One B-rep face of a CAD part: STEP entity #25646.
In plain terms, the planar face has unit normal (0, 0, 1).
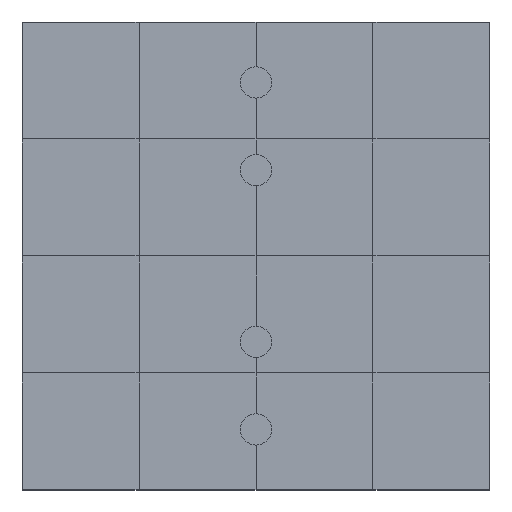
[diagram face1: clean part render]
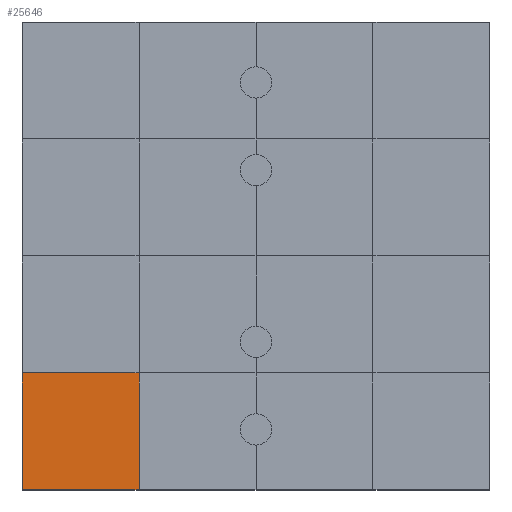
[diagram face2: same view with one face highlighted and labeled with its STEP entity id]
Its self-contained STEP definition (entity closure, numbers rounded to 3 decimals):
#25457 = VERTEX_POINT('',#25458);
#25458 = CARTESIAN_POINT('',(0.,0.,1.5));
#25465 = PLANE('',#25466);
#25466 = AXIS2_PLACEMENT_3D('',#25467,#25468,#25469);
#25467 = CARTESIAN_POINT('',(0.,0.,0.));
#25468 = DIRECTION('',(1.,0.,-0.));
#25469 = DIRECTION('',(0.,0.,1.));
#25477 = PLANE('',#25478);
#25478 = AXIS2_PLACEMENT_3D('',#25479,#25480,#25481);
#25479 = CARTESIAN_POINT('',(0.,0.,0.));
#25480 = DIRECTION('',(-0.,1.,0.));
#25481 = DIRECTION('',(0.,0.,1.));
#25518 = VERTEX_POINT('',#25519);
#25519 = CARTESIAN_POINT('',(0.,3.,1.5));
#25545 = EDGE_CURVE('',#25457,#25518,#25546,.T.);
#25546 = SURFACE_CURVE('',#25547,(#25551,#25558),.PCURVE_S1.);
#25547 = LINE('',#25548,#25549);
#25548 = CARTESIAN_POINT('',(0.,0.,1.5));
#25549 = VECTOR('',#25550,1.);
#25550 = DIRECTION('',(-0.,1.,0.));
#25551 = PCURVE('',#25465,#25552);
#25552 = DEFINITIONAL_REPRESENTATION('',(#25553),#25557);
#25553 = LINE('',#25554,#25555);
#25554 = CARTESIAN_POINT('',(1.5,0.));
#25555 = VECTOR('',#25556,1.);
#25556 = DIRECTION('',(0.,-1.));
#25557 = ( GEOMETRIC_REPRESENTATION_CONTEXT(2) 
PARAMETRIC_REPRESENTATION_CONTEXT() REPRESENTATION_CONTEXT('2D SPACE',''
  ) );
#25558 = PCURVE('',#25559,#25564);
#25559 = PLANE('',#25560);
#25560 = AXIS2_PLACEMENT_3D('',#25561,#25562,#25563);
#25561 = CARTESIAN_POINT('',(0.,0.,1.5));
#25562 = DIRECTION('',(0.,0.,1.));
#25563 = DIRECTION('',(1.,0.,-0.));
#25564 = DEFINITIONAL_REPRESENTATION('',(#25565),#25569);
#25565 = LINE('',#25566,#25567);
#25566 = CARTESIAN_POINT('',(0.,0.));
#25567 = VECTOR('',#25568,1.);
#25568 = DIRECTION('',(0.,1.));
#25569 = ( GEOMETRIC_REPRESENTATION_CONTEXT(2) 
PARAMETRIC_REPRESENTATION_CONTEXT() REPRESENTATION_CONTEXT('2D SPACE',''
  ) );
#25598 = EDGE_CURVE('',#25457,#25599,#25601,.T.);
#25599 = VERTEX_POINT('',#25600);
#25600 = CARTESIAN_POINT('',(3.,0.,1.5));
#25601 = SURFACE_CURVE('',#25602,(#25606,#25613),.PCURVE_S1.);
#25602 = LINE('',#25603,#25604);
#25603 = CARTESIAN_POINT('',(0.,0.,1.5));
#25604 = VECTOR('',#25605,1.);
#25605 = DIRECTION('',(1.,0.,-0.));
#25606 = PCURVE('',#25477,#25607);
#25607 = DEFINITIONAL_REPRESENTATION('',(#25608),#25612);
#25608 = LINE('',#25609,#25610);
#25609 = CARTESIAN_POINT('',(1.5,0.));
#25610 = VECTOR('',#25611,1.);
#25611 = DIRECTION('',(0.,1.));
#25612 = ( GEOMETRIC_REPRESENTATION_CONTEXT(2) 
PARAMETRIC_REPRESENTATION_CONTEXT() REPRESENTATION_CONTEXT('2D SPACE',''
  ) );
#25613 = PCURVE('',#25559,#25614);
#25614 = DEFINITIONAL_REPRESENTATION('',(#25615),#25619);
#25615 = LINE('',#25616,#25617);
#25616 = CARTESIAN_POINT('',(0.,0.));
#25617 = VECTOR('',#25618,1.);
#25618 = DIRECTION('',(1.,0.));
#25619 = ( GEOMETRIC_REPRESENTATION_CONTEXT(2) 
PARAMETRIC_REPRESENTATION_CONTEXT() REPRESENTATION_CONTEXT('2D SPACE',''
  ) );
#25646 = ADVANCED_FACE('',(#25647),#25559,.T.);
#25647 = FACE_BOUND('',#25648,.T.);
#25648 = EDGE_LOOP('',(#25649,#25650,#25651,#25679));
#25649 = ORIENTED_EDGE('',*,*,#25545,.F.);
#25650 = ORIENTED_EDGE('',*,*,#25598,.T.);
#25651 = ORIENTED_EDGE('',*,*,#25652,.T.);
#25652 = EDGE_CURVE('',#25599,#25653,#25655,.T.);
#25653 = VERTEX_POINT('',#25654);
#25654 = CARTESIAN_POINT('',(3.,3.,1.5));
#25655 = SURFACE_CURVE('',#25656,(#25660,#25667),.PCURVE_S1.);
#25656 = LINE('',#25657,#25658);
#25657 = CARTESIAN_POINT('',(3.,0.,1.5));
#25658 = VECTOR('',#25659,1.);
#25659 = DIRECTION('',(-0.,1.,0.));
#25660 = PCURVE('',#25559,#25661);
#25661 = DEFINITIONAL_REPRESENTATION('',(#25662),#25666);
#25662 = LINE('',#25663,#25664);
#25663 = CARTESIAN_POINT('',(3.,0.));
#25664 = VECTOR('',#25665,1.);
#25665 = DIRECTION('',(0.,1.));
#25666 = ( GEOMETRIC_REPRESENTATION_CONTEXT(2) 
PARAMETRIC_REPRESENTATION_CONTEXT() REPRESENTATION_CONTEXT('2D SPACE',''
  ) );
#25667 = PCURVE('',#25668,#25673);
#25668 = PLANE('',#25669);
#25669 = AXIS2_PLACEMENT_3D('',#25670,#25671,#25672);
#25670 = CARTESIAN_POINT('',(3.,0.,1.5));
#25671 = DIRECTION('',(0.,0.,1.));
#25672 = DIRECTION('',(1.,0.,-0.));
#25673 = DEFINITIONAL_REPRESENTATION('',(#25674),#25678);
#25674 = LINE('',#25675,#25676);
#25675 = CARTESIAN_POINT('',(0.,0.));
#25676 = VECTOR('',#25677,1.);
#25677 = DIRECTION('',(0.,1.));
#25678 = ( GEOMETRIC_REPRESENTATION_CONTEXT(2) 
PARAMETRIC_REPRESENTATION_CONTEXT() REPRESENTATION_CONTEXT('2D SPACE',''
  ) );
#25679 = ORIENTED_EDGE('',*,*,#25680,.F.);
#25680 = EDGE_CURVE('',#25518,#25653,#25681,.T.);
#25681 = SURFACE_CURVE('',#25682,(#25686,#25693),.PCURVE_S1.);
#25682 = LINE('',#25683,#25684);
#25683 = CARTESIAN_POINT('',(0.,3.,1.5));
#25684 = VECTOR('',#25685,1.);
#25685 = DIRECTION('',(1.,0.,-0.));
#25686 = PCURVE('',#25559,#25687);
#25687 = DEFINITIONAL_REPRESENTATION('',(#25688),#25692);
#25688 = LINE('',#25689,#25690);
#25689 = CARTESIAN_POINT('',(0.,3.));
#25690 = VECTOR('',#25691,1.);
#25691 = DIRECTION('',(1.,0.));
#25692 = ( GEOMETRIC_REPRESENTATION_CONTEXT(2) 
PARAMETRIC_REPRESENTATION_CONTEXT() REPRESENTATION_CONTEXT('2D SPACE',''
  ) );
#25693 = PCURVE('',#25694,#25699);
#25694 = PLANE('',#25695);
#25695 = AXIS2_PLACEMENT_3D('',#25696,#25697,#25698);
#25696 = CARTESIAN_POINT('',(0.,3.,1.5));
#25697 = DIRECTION('',(0.,0.,1.));
#25698 = DIRECTION('',(1.,0.,-0.));
#25699 = DEFINITIONAL_REPRESENTATION('',(#25700),#25704);
#25700 = LINE('',#25701,#25702);
#25701 = CARTESIAN_POINT('',(0.,0.));
#25702 = VECTOR('',#25703,1.);
#25703 = DIRECTION('',(1.,0.));
#25704 = ( GEOMETRIC_REPRESENTATION_CONTEXT(2) 
PARAMETRIC_REPRESENTATION_CONTEXT() REPRESENTATION_CONTEXT('2D SPACE',''
  ) );
